VERSION 5.8 ;
BUSBITCHARS "[]" ;
DIVIDERCHAR "/" ;
UNITS
    DATABASE MICRONS 1000 ;
END UNITS

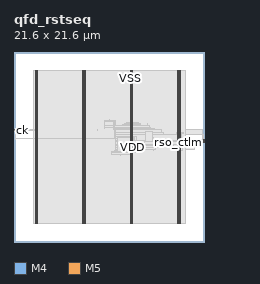
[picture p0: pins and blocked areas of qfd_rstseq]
MACRO qfd_rstseq
  FOREIGN qfd_rstseq 0 0 ;
  CLASS BLOCK ;
  SIZE 21.6 BY 21.6 ;
  PIN ck
    DIRECTION INPUT ;
    USE SIGNAL ;
    PORT
      LAYER M4 ;
        RECT  0 12.624 0.084 12.648 ;
    END
  END ck
  PIN rsi
    DIRECTION INPUT ;
    USE SIGNAL ;
    PORT
      LAYER M4 ;
        RECT  0 12.72 0.084 12.744 ;
    END
  END rsi
  PIN rso_ctlm
    DIRECTION OUTPUT ;
    USE SIGNAL ;
    PORT
      LAYER M4 ;
        RECT  21.516 11.28 21.6 11.304 ;
    END
  END rso_ctlm
  PIN rso_f
    DIRECTION OUTPUT ;
    USE SIGNAL ;
    PORT
      LAYER M4 ;
        RECT  21.516 11.376 21.6 11.4 ;
    END
  END rso_f
  PIN rso_io
    DIRECTION OUTPUT ;
    USE SIGNAL ;
    PORT
      LAYER M4 ;
        RECT  21.516 11.472 21.6 11.496 ;
    END
  END rso_io
  PIN rso_s
    DIRECTION OUTPUT ;
    USE SIGNAL ;
    PORT
      LAYER M4 ;
        RECT  21.516 11.568 21.6 11.592 ;
    END
  END rso_s
  PIN rso_seq
    DIRECTION OUTPUT ;
    USE SIGNAL ;
    PORT
      LAYER M4 ;
        RECT  21.516 11.664 21.6 11.688 ;
    END
  END rso_seq
  PIN VDD
    DIRECTION INOUT ;
    USE POWER ;
    PORT
      LAYER M5 ;
        RECT  18.792 2.151 18.912 19.449 ;
        RECT  13.392 2.151 13.512 19.449 ;
        RECT  7.992 2.151 8.112 19.449 ;
        RECT  2.592 2.151 2.712 19.449 ;
    END
  END VDD
  PIN VSS
    DIRECTION INOUT ;
    USE GROUND ;
    PORT
      LAYER M5 ;
        RECT  18.6 2.137 18.72 19.463 ;
        RECT  13.2 2.137 13.32 19.463 ;
        RECT  7.8 2.137 7.92 19.463 ;
        RECT  2.4 2.137 2.52 19.463 ;
    END
  END VSS
  # OT_OBS_CLOSED layer=M5 d_um=1.536 added=2
  OBS
    LAYER RVTN ;
     RECT  2.16 2.16 19.44 2.295 ;
     RECT  2.16 2.565 19.44 2.835 ;
     RECT  2.16 3.105 19.44 3.375 ;
     RECT  2.16 3.645 19.44 3.915 ;
     RECT  2.16 4.185 19.44 4.455 ;
     RECT  2.16 4.725 19.44 4.995 ;
     RECT  2.16 5.265 19.44 5.535 ;
     RECT  2.16 5.805 19.44 6.075 ;
     RECT  2.16 6.345 19.44 6.615 ;
     RECT  2.16 6.885 19.44 7.155 ;
     RECT  2.16 7.425 19.44 7.695 ;
     RECT  2.16 7.965 19.44 8.235 ;
     RECT  2.16 8.505 19.44 8.775 ;
     RECT  2.16 9.045 19.44 9.315 ;
     RECT  2.16 9.585 19.44 9.855 ;
     RECT  2.16 10.125 19.44 10.395 ;
     RECT  2.16 10.665 19.44 10.935 ;
     RECT  2.16 11.205 19.44 11.475 ;
     RECT  2.16 11.745 19.44 12.015 ;
     RECT  2.16 12.285 19.44 12.555 ;
     RECT  2.16 12.825 19.44 13.095 ;
     RECT  2.16 13.365 19.44 13.635 ;
     RECT  2.16 13.905 19.44 14.175 ;
     RECT  2.16 14.445 19.44 14.715 ;
     RECT  2.16 14.985 19.44 15.255 ;
     RECT  2.16 15.525 19.44 15.795 ;
     RECT  2.16 16.065 19.44 16.335 ;
     RECT  2.16 16.605 19.44 16.875 ;
     RECT  2.16 17.145 19.44 17.415 ;
     RECT  2.16 17.685 19.44 17.955 ;
     RECT  2.16 18.225 19.44 18.495 ;
     RECT  2.16 18.765 19.44 19.035 ;
     RECT  2.16 19.305 19.44 19.44 ;
    LAYER RVTP ;
     RECT  2.16 2.295 19.44 2.565 ;
     RECT  2.16 2.835 19.44 3.105 ;
     RECT  2.16 3.375 19.44 3.645 ;
     RECT  2.16 3.915 19.44 4.185 ;
     RECT  2.16 4.455 19.44 4.725 ;
     RECT  2.16 4.995 19.44 5.265 ;
     RECT  2.16 5.535 19.44 5.805 ;
     RECT  2.16 6.075 19.44 6.345 ;
     RECT  2.16 6.615 19.44 6.885 ;
     RECT  2.16 7.155 19.44 7.425 ;
     RECT  2.16 7.695 19.44 7.965 ;
     RECT  2.16 8.235 19.44 8.505 ;
     RECT  2.16 8.775 19.44 9.045 ;
     RECT  2.16 9.315 19.44 9.585 ;
     RECT  2.16 9.855 19.44 10.125 ;
     RECT  2.16 10.395 19.44 10.665 ;
     RECT  2.16 10.935 19.44 11.205 ;
     RECT  2.16 11.475 19.44 11.745 ;
     RECT  2.16 12.015 19.44 12.285 ;
     RECT  2.16 12.555 19.44 12.825 ;
     RECT  2.16 13.095 19.44 13.365 ;
     RECT  2.16 13.635 19.44 13.905 ;
     RECT  2.16 14.175 19.44 14.445 ;
     RECT  2.16 14.715 19.44 14.985 ;
     RECT  2.16 15.255 19.44 15.525 ;
     RECT  2.16 15.795 19.44 16.065 ;
     RECT  2.16 16.335 19.44 16.605 ;
     RECT  2.16 16.875 19.44 17.145 ;
     RECT  2.16 17.415 19.44 17.685 ;
     RECT  2.16 17.955 19.44 18.225 ;
     RECT  2.16 18.495 19.44 18.765 ;
     RECT  2.16 19.035 19.44 19.305 ;
    LAYER M1 ;
     RECT  2.16 2.151 19.44 19.449 ;
    LAYER M2 ;
     RECT  2.16 2.151 19.44 19.449 ;
     RECT  19.44 10.476 20.507 11.394 ;
     RECT  20.507 10.476 20.543 10.764 ;
     RECT  20.543 10.746 20.579 10.764 ;
     RECT  19.44 12.186 21.479 12.744 ;
     RECT  21.479 12.186 21.515 12.204 ;
    LAYER M3 ;
     RECT  2.415 2.143 2.505 2.413 ;
     RECT  7.815 2.143 7.905 2.413 ;
     RECT  13.215 2.143 13.305 2.413 ;
     RECT  18.615 2.143 18.705 2.413 ;
     RECT  12.06 9.859 12.078 9.895 ;
     RECT  13.215 2.413 13.497 9.895 ;
     RECT  11.88 9.895 12.078 9.931 ;
     RECT  13.104 9.895 13.497 9.931 ;
     RECT  11.124 9.931 13.497 10.201 ;
     RECT  14.328 10.165 14.346 10.201 ;
     RECT  11.124 10.201 14.346 10.301 ;
     RECT  11.412 10.301 14.346 10.427 ;
     RECT  18.615 2.413 18.897 10.435 ;
     RECT  11.484 10.427 14.346 10.471 ;
     RECT  15.804 10.435 15.822 10.471 ;
     RECT  11.484 10.471 16.038 10.705 ;
     RECT  20.52 10.471 20.538 10.741 ;
     RECT  11.484 10.705 16.686 10.769 ;
     RECT  18.108 10.435 19.134 10.859 ;
     RECT  11.556 10.769 16.686 11.011 ;
     RECT  11.556 11.011 17.154 11.137 ;
     RECT  18.108 10.859 19.098 11.137 ;
     RECT  20.52 10.741 20.574 11.371 ;
     RECT  20.484 11.371 20.574 11.408 ;
     RECT  11.556 11.137 19.098 11.471 ;
     RECT  11.556 11.471 19.062 11.515 ;
     RECT  21.492 11.467 21.51 11.563 ;
     RECT  20.556 11.408 20.574 11.693 ;
     RECT  11.484 11.515 19.062 12.209 ;
     RECT  21.456 11.563 21.51 12.209 ;
     RECT  18.216 12.209 19.062 12.245 ;
     RECT  18.432 12.245 19.062 12.361 ;
     RECT  11.484 12.209 16.974 12.479 ;
     RECT  18.432 12.361 19.242 12.479 ;
     RECT  2.415 2.413 2.697 12.715 ;
     RECT  21.456 12.209 21.474 12.749 ;
     RECT  2.412 12.715 2.697 12.785 ;
     RECT  11.484 12.479 16.722 12.785 ;
     RECT  9.468 12.721 9.486 12.821 ;
     RECT  11.484 12.785 16.002 12.829 ;
     RECT  11.304 12.829 16.002 12.857 ;
     RECT  18.615 12.479 18.954 12.893 ;
     RECT  11.304 12.857 15.534 13.019 ;
     RECT  10.296 12.901 10.314 13.027 ;
     RECT  11.304 13.019 15.426 13.027 ;
     RECT  10.296 13.027 15.426 13.289 ;
     RECT  12.312 13.289 14.346 13.361 ;
     RECT  12.564 13.361 14.346 13.469 ;
     RECT  15.12 13.289 15.138 13.469 ;
     RECT  12.816 13.469 14.202 13.595 ;
     RECT  10.296 13.289 11.538 13.675 ;
     RECT  10.26 13.675 11.538 13.829 ;
     RECT  10.836 13.829 10.998 13.865 ;
     RECT  10.836 13.865 10.854 13.901 ;
     RECT  2.415 12.785 2.697 19.187 ;
     RECT  7.815 2.413 8.097 19.187 ;
     RECT  13.215 13.595 13.497 19.187 ;
     RECT  18.615 12.893 18.897 19.187 ;
     RECT  2.415 19.187 2.505 19.457 ;
     RECT  7.815 19.187 7.905 19.457 ;
     RECT  13.215 19.187 13.305 19.457 ;
     RECT  18.615 19.187 18.705 19.457 ;
    LAYER M4 ;
     RECT  0.06 12.624 0.133 12.744 ;
     RECT  0.133 11.712 0.179 12.744 ;
     RECT  0.179 11.712 2.408 11.736 ;
     RECT  0.179 12.72 2.408 12.744 ;
     RECT  2.408 2.148 2.512 19.452 ;
     RECT  2.512 2.418 2.704 19.182 ;
     RECT  2.704 11.712 7.808 11.736 ;
     RECT  7.808 2.148 7.912 19.452 ;
     RECT  7.912 2.418 8.104 19.182 ;
     RECT  10.249 13.68 11.293 13.704 ;
     RECT  8.104 11.712 11.413 11.736 ;
     RECT  11.293 12.864 11.413 13.704 ;
     RECT  11.413 11.712 11.459 13.704 ;
     RECT  11.459 11.712 11.513 12.12 ;
     RECT  11.113 10.272 12.013 10.296 ;
     RECT  12.013 10.272 12.053 10.392 ;
     RECT  12.053 10.368 12.301 10.392 ;
     RECT  11.513 11.712 12.301 11.976 ;
     RECT  12.301 10.368 13.208 11.976 ;
     RECT  11.459 13.248 13.208 13.272 ;
     RECT  13.208 2.148 13.312 19.452 ;
     RECT  13.312 2.418 13.504 19.182 ;
     RECT  13.504 10.368 13.601 11.976 ;
     RECT  13.601 10.896 13.745 11.976 ;
     RECT  13.745 11.328 13.925 11.976 ;
     RECT  13.925 11.328 14.867 11.592 ;
     RECT  14.867 11.376 14.965 11.592 ;
     RECT  14.965 11.376 15.725 12.552 ;
     RECT  15.725 11.376 15.833 11.832 ;
     RECT  15.833 11.376 15.865 11.736 ;
     RECT  15.865 11.04 16.013 11.736 ;
     RECT  16.013 11.04 16.913 11.592 ;
     RECT  16.913 11.568 17.129 11.592 ;
     RECT  18.608 2.148 18.712 19.452 ;
     RECT  18.712 2.418 18.904 19.182 ;
     RECT  20.473 11.376 20.509 11.4 ;
     RECT  20.509 11.28 20.545 11.4 ;
     RECT  20.545 11.28 21.564 11.688 ;
    LAYER M5 ;
     RECT  2.4 2.137 2.52 2.151 ;
     RECT  7.8 2.137 7.92 2.151 ;
     RECT  13.2 2.137 13.32 2.151 ;
     RECT  18.6 2.137 18.72 2.151 ;
     RECT  14.832 11.317 14.856 11.507 ;
     RECT  11.712 10.261 11.736 11.843 ;
     RECT  0.144 11.701 0.168 12.659 ;
     RECT  11.424 12.085 11.448 13.715 ;
     RECT  2.4 2.151 2.712 19.449 ;
     RECT  7.8 2.151 8.112 19.449 ;
     RECT  13.2 2.151 13.512 19.449 ;
     RECT  18.6 2.151 18.912 19.449 ;
     RECT  2.4 19.449 2.52 19.463 ;
     RECT  7.8 19.449 7.92 19.463 ;
     RECT  13.2 19.449 13.32 19.463 ;
     RECT  18.6 19.449 18.72 19.463 ;
     RECT  11.736 10.261 13.2 11.843 ;
     RECT  13.512 11.317 14.832 11.507 ;
  END
END qfd_rstseq
END LIBRARY
